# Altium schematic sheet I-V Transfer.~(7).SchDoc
size A4

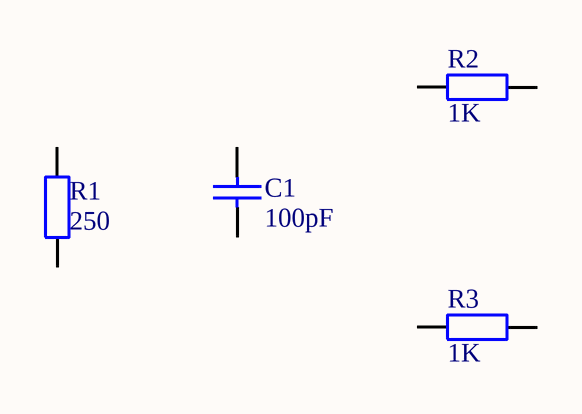
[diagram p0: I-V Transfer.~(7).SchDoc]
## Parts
C1  value 100pF  [RAD-0.3]  (hidden comment: Cap)
R1  value 250  [AXIAL-0.4]  (hidden comment: Res2)
R2  value 1K  [AXIAL-0.4]  (hidden comment: Res2)
R3  value 1K  [AXIAL-0.4]  (hidden comment: Res2)

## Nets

Not connected (* = marked no-connect by the designer): C1 1 2; R1 1 2; R2 1 2; R3 1 2

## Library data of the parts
C1 = Cap: Capacitor
R1-R3 = Res2: Resistor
